VERSION 5.7 ;
BUSBITCHARS "[]" ;
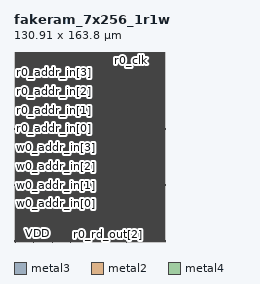
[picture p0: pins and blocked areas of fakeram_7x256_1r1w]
MACRO fakeram_7x256_1r1w
  FOREIGN fakeram_7x256_1r1w 0 0 ;
  SYMMETRY X Y R90 ;
  SIZE 130.910 BY 163.800 ;
  CLASS BLOCK ;
  PIN w0_wd_in[0]
    DIRECTION INPUT ;
    USE SIGNAL ;
    SHAPE ABUTMENT ;
    PORT
      LAYER metal3 ;
      RECT 0.000 0.805 0.210 0.875 ;
    END
  END w0_wd_in[0]
  PIN w0_wd_in[1]
    DIRECTION INPUT ;
    USE SIGNAL ;
    SHAPE ABUTMENT ;
    PORT
      LAYER metal3 ;
      RECT 0.000 16.905 0.210 16.975 ;
    END
  END w0_wd_in[1]
  PIN w0_wd_in[2]
    DIRECTION INPUT ;
    USE SIGNAL ;
    SHAPE ABUTMENT ;
    PORT
      LAYER metal3 ;
      RECT 130.700 0.805 130.910 0.875 ;
    END
  END w0_wd_in[2]
  PIN w0_wd_in[3]
    DIRECTION INPUT ;
    USE SIGNAL ;
    SHAPE ABUTMENT ;
    PORT
      LAYER metal3 ;
      RECT 130.700 16.905 130.910 16.975 ;
    END
  END w0_wd_in[3]
  PIN w0_wd_in[4]
    DIRECTION INPUT ;
    USE SIGNAL ;
    SHAPE ABUTMENT ;
    PORT
      LAYER metal2 ;
      RECT 1.105 0.000 1.175 0.210 ;
    END
  END w0_wd_in[4]
  PIN w0_wd_in[5]
    DIRECTION INPUT ;
    USE SIGNAL ;
    SHAPE ABUTMENT ;
    PORT
      LAYER metal2 ;
      RECT 17.065 0.000 17.135 0.210 ;
    END
  END w0_wd_in[5]
  PIN w0_wd_in[6]
    DIRECTION INPUT ;
    USE SIGNAL ;
    SHAPE ABUTMENT ;
    PORT
      LAYER metal2 ;
      RECT 33.025 0.000 33.095 0.210 ;
    END
  END w0_wd_in[6]
  PIN r0_rd_out[0]
    DIRECTION OUTPUT ;
    USE SIGNAL ;
    SHAPE ABUTMENT ;
    PORT
      LAYER metal2 ;
      RECT 48.985 0.000 49.055 0.210 ;
    END
  END r0_rd_out[0]
  PIN r0_rd_out[1]
    DIRECTION OUTPUT ;
    USE SIGNAL ;
    SHAPE ABUTMENT ;
    PORT
      LAYER metal2 ;
      RECT 64.945 0.000 65.015 0.210 ;
    END
  END r0_rd_out[1]
  PIN r0_rd_out[2]
    DIRECTION OUTPUT ;
    USE SIGNAL ;
    SHAPE ABUTMENT ;
    PORT
      LAYER metal2 ;
      RECT 80.905 0.000 80.975 0.210 ;
    END
  END r0_rd_out[2]
  PIN r0_rd_out[3]
    DIRECTION OUTPUT ;
    USE SIGNAL ;
    SHAPE ABUTMENT ;
    PORT
      LAYER metal2 ;
      RECT 96.865 0.000 96.935 0.210 ;
    END
  END r0_rd_out[3]
  PIN r0_rd_out[4]
    DIRECTION OUTPUT ;
    USE SIGNAL ;
    SHAPE ABUTMENT ;
    PORT
      LAYER metal2 ;
      RECT 1.105 163.590 1.175 163.800 ;
    END
  END r0_rd_out[4]
  PIN r0_rd_out[5]
    DIRECTION OUTPUT ;
    USE SIGNAL ;
    SHAPE ABUTMENT ;
    PORT
      LAYER metal2 ;
      RECT 15.355 163.590 15.425 163.800 ;
    END
  END r0_rd_out[5]
  PIN r0_rd_out[6]
    DIRECTION OUTPUT ;
    USE SIGNAL ;
    SHAPE ABUTMENT ;
    PORT
      LAYER metal2 ;
      RECT 29.605 163.590 29.675 163.800 ;
    END
  END r0_rd_out[6]
  PIN w0_addr_in[0]
    DIRECTION INPUT ;
    USE SIGNAL ;
    SHAPE ABUTMENT ;
    PORT
      LAYER metal3 ;
      RECT 0.000 33.005 0.210 33.075 ;
    END
  END w0_addr_in[0]
  PIN w0_addr_in[1]
    DIRECTION INPUT ;
    USE SIGNAL ;
    SHAPE ABUTMENT ;
    PORT
      LAYER metal3 ;
      RECT 0.000 49.105 0.210 49.175 ;
    END
  END w0_addr_in[1]
  PIN w0_addr_in[2]
    DIRECTION INPUT ;
    USE SIGNAL ;
    SHAPE ABUTMENT ;
    PORT
      LAYER metal3 ;
      RECT 0.000 65.205 0.210 65.275 ;
    END
  END w0_addr_in[2]
  PIN w0_addr_in[3]
    DIRECTION INPUT ;
    USE SIGNAL ;
    SHAPE ABUTMENT ;
    PORT
      LAYER metal3 ;
      RECT 0.000 81.305 0.210 81.375 ;
    END
  END w0_addr_in[3]
  PIN w0_addr_in[4]
    DIRECTION INPUT ;
    USE SIGNAL ;
    SHAPE ABUTMENT ;
    PORT
      LAYER metal3 ;
      RECT 130.700 33.005 130.910 33.075 ;
    END
  END w0_addr_in[4]
  PIN w0_addr_in[5]
    DIRECTION INPUT ;
    USE SIGNAL ;
    SHAPE ABUTMENT ;
    PORT
      LAYER metal3 ;
      RECT 130.700 49.105 130.910 49.175 ;
    END
  END w0_addr_in[5]
  PIN w0_addr_in[6]
    DIRECTION INPUT ;
    USE SIGNAL ;
    SHAPE ABUTMENT ;
    PORT
      LAYER metal3 ;
      RECT 130.700 65.205 130.910 65.275 ;
    END
  END w0_addr_in[6]
  PIN w0_addr_in[7]
    DIRECTION INPUT ;
    USE SIGNAL ;
    SHAPE ABUTMENT ;
    PORT
      LAYER metal3 ;
      RECT 130.700 81.305 130.910 81.375 ;
    END
  END w0_addr_in[7]
  PIN r0_addr_in[0]
    DIRECTION INPUT ;
    USE SIGNAL ;
    SHAPE ABUTMENT ;
    PORT
      LAYER metal3 ;
      RECT 0.000 97.405 0.210 97.475 ;
    END
  END r0_addr_in[0]
  PIN r0_addr_in[1]
    DIRECTION INPUT ;
    USE SIGNAL ;
    SHAPE ABUTMENT ;
    PORT
      LAYER metal3 ;
      RECT 0.000 113.505 0.210 113.575 ;
    END
  END r0_addr_in[1]
  PIN r0_addr_in[2]
    DIRECTION INPUT ;
    USE SIGNAL ;
    SHAPE ABUTMENT ;
    PORT
      LAYER metal3 ;
      RECT 0.000 129.605 0.210 129.675 ;
    END
  END r0_addr_in[2]
  PIN r0_addr_in[3]
    DIRECTION INPUT ;
    USE SIGNAL ;
    SHAPE ABUTMENT ;
    PORT
      LAYER metal3 ;
      RECT 0.000 145.705 0.210 145.775 ;
    END
  END r0_addr_in[3]
  PIN r0_addr_in[4]
    DIRECTION INPUT ;
    USE SIGNAL ;
    SHAPE ABUTMENT ;
    PORT
      LAYER metal3 ;
      RECT 130.700 97.405 130.910 97.475 ;
    END
  END r0_addr_in[4]
  PIN r0_addr_in[5]
    DIRECTION INPUT ;
    USE SIGNAL ;
    SHAPE ABUTMENT ;
    PORT
      LAYER metal3 ;
      RECT 130.700 113.505 130.910 113.575 ;
    END
  END r0_addr_in[5]
  PIN r0_addr_in[6]
    DIRECTION INPUT ;
    USE SIGNAL ;
    SHAPE ABUTMENT ;
    PORT
      LAYER metal3 ;
      RECT 130.700 129.605 130.910 129.675 ;
    END
  END r0_addr_in[6]
  PIN r0_addr_in[7]
    DIRECTION INPUT ;
    USE SIGNAL ;
    SHAPE ABUTMENT ;
    PORT
      LAYER metal3 ;
      RECT 130.700 145.705 130.910 145.775 ;
    END
  END r0_addr_in[7]
  PIN w0_we_in
    DIRECTION INPUT ;
    USE SIGNAL ;
    SHAPE ABUTMENT ;
    PORT
      LAYER metal2 ;
      RECT 43.855 163.590 43.925 163.800 ;
    END
  END w0_we_in
  PIN w0_ce_in
    DIRECTION INPUT ;
    USE SIGNAL ;
    SHAPE ABUTMENT ;
    PORT
      LAYER metal2 ;
      RECT 58.105 163.590 58.175 163.800 ;
    END
  END w0_ce_in
  PIN w0_clk
    DIRECTION INPUT ;
    USE SIGNAL ;
    SHAPE ABUTMENT ;
    PORT
      LAYER metal2 ;
      RECT 72.355 163.590 72.425 163.800 ;
    END
  END w0_clk
  PIN r0_ce_in
    DIRECTION INPUT ;
    USE SIGNAL ;
    SHAPE ABUTMENT ;
    PORT
      LAYER metal2 ;
      RECT 86.605 163.590 86.675 163.800 ;
    END
  END r0_ce_in
  PIN r0_clk
    DIRECTION INPUT ;
    USE SIGNAL ;
    SHAPE ABUTMENT ;
    PORT
      LAYER metal2 ;
      RECT 100.855 163.590 100.925 163.800 ;
    END
  END r0_clk
  PIN VSS
    DIRECTION INOUT ;
    USE GROUND ;
    PORT
      LAYER metal4 ;
      RECT 1.000 0.840 1.280 162.960 ;
      RECT 3.240 0.840 3.520 162.960 ;
      RECT 5.480 0.840 5.760 162.960 ;
      RECT 7.720 0.840 8.000 162.960 ;
      RECT 9.960 0.840 10.240 162.960 ;
      RECT 12.200 0.840 12.480 162.960 ;
      RECT 14.440 0.840 14.720 162.960 ;
      RECT 16.680 0.840 16.960 162.960 ;
      RECT 18.920 0.840 19.200 162.960 ;
      RECT 21.160 0.840 21.440 162.960 ;
      RECT 23.400 0.840 23.680 162.960 ;
      RECT 25.640 0.840 25.920 162.960 ;
      RECT 27.880 0.840 28.160 162.960 ;
      RECT 30.120 0.840 30.400 162.960 ;
      RECT 32.360 0.840 32.640 162.960 ;
      RECT 34.600 0.840 34.880 162.960 ;
      RECT 36.840 0.840 37.120 162.960 ;
      RECT 39.080 0.840 39.360 162.960 ;
      RECT 41.320 0.840 41.600 162.960 ;
      RECT 43.560 0.840 43.840 162.960 ;
      RECT 45.800 0.840 46.080 162.960 ;
      RECT 48.040 0.840 48.320 162.960 ;
      RECT 50.280 0.840 50.560 162.960 ;
      RECT 52.520 0.840 52.800 162.960 ;
      RECT 54.760 0.840 55.040 162.960 ;
      RECT 57.000 0.840 57.280 162.960 ;
      RECT 59.240 0.840 59.520 162.960 ;
      RECT 61.480 0.840 61.760 162.960 ;
      RECT 63.720 0.840 64.000 162.960 ;
      RECT 65.960 0.840 66.240 162.960 ;
      RECT 68.200 0.840 68.480 162.960 ;
      RECT 70.440 0.840 70.720 162.960 ;
      RECT 72.680 0.840 72.960 162.960 ;
      RECT 74.920 0.840 75.200 162.960 ;
      RECT 77.160 0.840 77.440 162.960 ;
      RECT 79.400 0.840 79.680 162.960 ;
      RECT 81.640 0.840 81.920 162.960 ;
      RECT 83.880 0.840 84.160 162.960 ;
      RECT 86.120 0.840 86.400 162.960 ;
      RECT 88.360 0.840 88.640 162.960 ;
      RECT 90.600 0.840 90.880 162.960 ;
      RECT 92.840 0.840 93.120 162.960 ;
      RECT 95.080 0.840 95.360 162.960 ;
      RECT 97.320 0.840 97.600 162.960 ;
      RECT 99.560 0.840 99.840 162.960 ;
      RECT 101.800 0.840 102.080 162.960 ;
      RECT 104.040 0.840 104.320 162.960 ;
      RECT 106.280 0.840 106.560 162.960 ;
      RECT 108.520 0.840 108.800 162.960 ;
      RECT 110.760 0.840 111.040 162.960 ;
      RECT 113.000 0.840 113.280 162.960 ;
      RECT 115.240 0.840 115.520 162.960 ;
      RECT 117.480 0.840 117.760 162.960 ;
      RECT 119.720 0.840 120.000 162.960 ;
      RECT 121.960 0.840 122.240 162.960 ;
      RECT 124.200 0.840 124.480 162.960 ;
      RECT 126.440 0.840 126.720 162.960 ;
      RECT 128.680 0.840 128.960 162.960 ;
    END
  END VSS
  PIN VDD
    DIRECTION INOUT ;
    USE POWER ;
    PORT
      LAYER metal4 ;
      RECT 2.120 0.840 2.400 162.960 ;
      RECT 4.360 0.840 4.640 162.960 ;
      RECT 6.600 0.840 6.880 162.960 ;
      RECT 8.840 0.840 9.120 162.960 ;
      RECT 11.080 0.840 11.360 162.960 ;
      RECT 13.320 0.840 13.600 162.960 ;
      RECT 15.560 0.840 15.840 162.960 ;
      RECT 17.800 0.840 18.080 162.960 ;
      RECT 20.040 0.840 20.320 162.960 ;
      RECT 22.280 0.840 22.560 162.960 ;
      RECT 24.520 0.840 24.800 162.960 ;
      RECT 26.760 0.840 27.040 162.960 ;
      RECT 29.000 0.840 29.280 162.960 ;
      RECT 31.240 0.840 31.520 162.960 ;
      RECT 33.480 0.840 33.760 162.960 ;
      RECT 35.720 0.840 36.000 162.960 ;
      RECT 37.960 0.840 38.240 162.960 ;
      RECT 40.200 0.840 40.480 162.960 ;
      RECT 42.440 0.840 42.720 162.960 ;
      RECT 44.680 0.840 44.960 162.960 ;
      RECT 46.920 0.840 47.200 162.960 ;
      RECT 49.160 0.840 49.440 162.960 ;
      RECT 51.400 0.840 51.680 162.960 ;
      RECT 53.640 0.840 53.920 162.960 ;
      RECT 55.880 0.840 56.160 162.960 ;
      RECT 58.120 0.840 58.400 162.960 ;
      RECT 60.360 0.840 60.640 162.960 ;
      RECT 62.600 0.840 62.880 162.960 ;
      RECT 64.840 0.840 65.120 162.960 ;
      RECT 67.080 0.840 67.360 162.960 ;
      RECT 69.320 0.840 69.600 162.960 ;
      RECT 71.560 0.840 71.840 162.960 ;
      RECT 73.800 0.840 74.080 162.960 ;
      RECT 76.040 0.840 76.320 162.960 ;
      RECT 78.280 0.840 78.560 162.960 ;
      RECT 80.520 0.840 80.800 162.960 ;
      RECT 82.760 0.840 83.040 162.960 ;
      RECT 85.000 0.840 85.280 162.960 ;
      RECT 87.240 0.840 87.520 162.960 ;
      RECT 89.480 0.840 89.760 162.960 ;
      RECT 91.720 0.840 92.000 162.960 ;
      RECT 93.960 0.840 94.240 162.960 ;
      RECT 96.200 0.840 96.480 162.960 ;
      RECT 98.440 0.840 98.720 162.960 ;
      RECT 100.680 0.840 100.960 162.960 ;
      RECT 102.920 0.840 103.200 162.960 ;
      RECT 105.160 0.840 105.440 162.960 ;
      RECT 107.400 0.840 107.680 162.960 ;
      RECT 109.640 0.840 109.920 162.960 ;
      RECT 111.880 0.840 112.160 162.960 ;
      RECT 114.120 0.840 114.400 162.960 ;
      RECT 116.360 0.840 116.640 162.960 ;
      RECT 118.600 0.840 118.880 162.960 ;
      RECT 120.840 0.840 121.120 162.960 ;
      RECT 123.080 0.840 123.360 162.960 ;
      RECT 125.320 0.840 125.600 162.960 ;
      RECT 127.560 0.840 127.840 162.960 ;
      RECT 129.800 0.840 130.080 162.960 ;
    END
  END VDD
  OBS
    LAYER metal1 ;
    RECT 0 0 130.910 163.800 ;
    LAYER metal2 ;
    RECT 0 0 130.910 163.800 ;
    LAYER metal3 ;
    RECT 0 0 130.910 163.800 ;
    LAYER metal4 ;
    RECT 0 0 130.910 163.800 ;
    LAYER OVERLAP ;
    RECT 0 0 130.910 163.800 ;
  END
END fakeram_7x256_1r1w

END LIBRARY
